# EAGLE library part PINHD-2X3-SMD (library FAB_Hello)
PIN HEADER

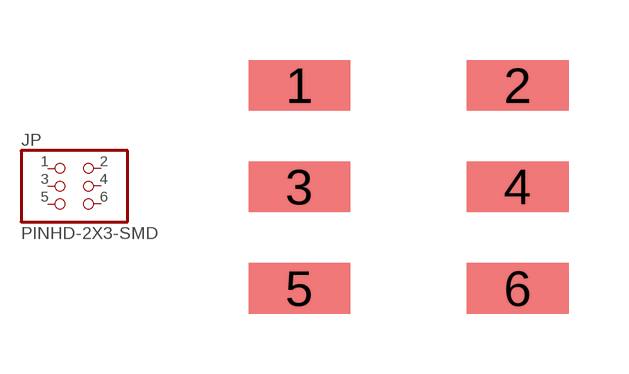
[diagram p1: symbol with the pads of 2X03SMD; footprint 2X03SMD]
Designator prefix JP

## PINHD-2X3-SMD  [2X03SMD]
1  1  pas
2  2  pas
3  3  pas
4  4  pas
5  5  pas
6  6  pas

## Footprint 2X03SMD (pad centres in mm)
smd 2.54 x 1.27: 1 -2.54,2.54; 2 2.92,2.54; 3 -2.54,0; 4 2.92,0; 5 -2.54,-2.54; 6 2.92,-2.54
